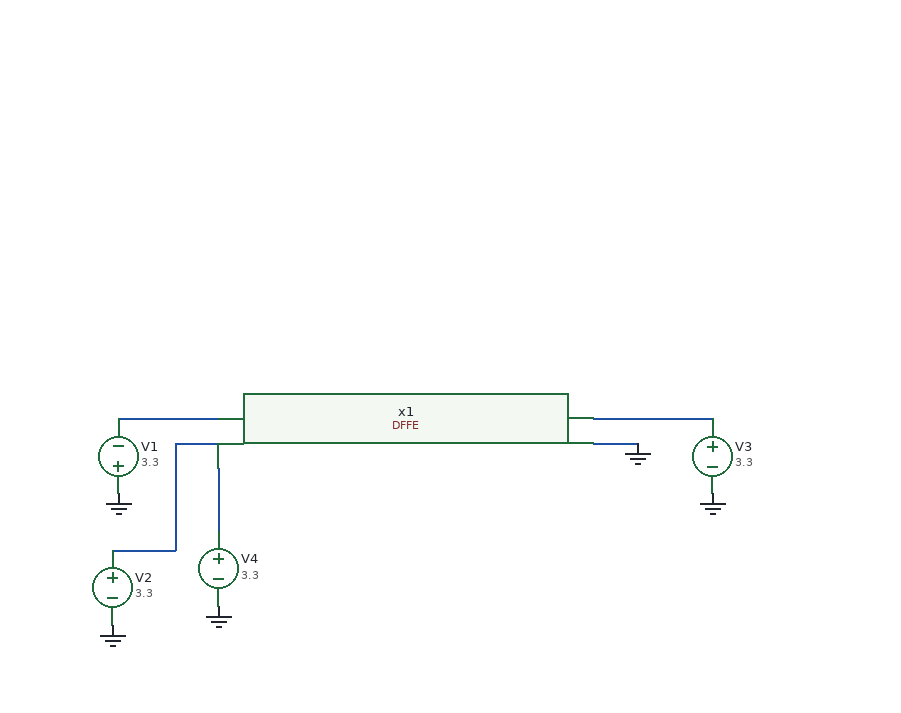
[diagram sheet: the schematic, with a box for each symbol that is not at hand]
v {xschem version=3.4.7 file_version=1.2}
G {}
K {}
V {}
S {}
E {}
N -1165 -2135 -1130 -2135 {lab=GND}
N -1545 -2155 -1465 -2155 {lab=#net1}
N -1550 -2050 -1500 -2050 {lab=#net2}
N -1500 -2135 -1500 -2050 {lab=#net2}
N -1500 -2135 -1465 -2135 {lab=#net2}
N -1165 -2155 -1070 -2155 {lab=#net3}
N -1465 -2115 -1465 -2065 {lab=#net4}
C {DFFE/DFFE.sym} -1315 -2125 0 0 {name=x1}
C {vsource.sym} -1550 -2020 0 0 {name=V2 value=3.3 savecurrent=false}
C {vsource.sym} -1070 -2125 0 0 {name=V3 value=3.3 savecurrent=false}
C {gnd.sym} -1545 -2095 0 0 {name=l1 lab=GND}
C {gnd.sym} -1550 -1990 0 0 {name=l2 lab=GND}
C {gnd.sym} -1070 -2095 0 0 {name=l3 lab=GND}
C {gnd.sym} -1130 -2135 0 0 {name=l4 lab=GND}
C {gnd.sym} -1465 -2005 0 0 {name=l5 lab=GND}
C {vsource.sym} -1465 -2035 0 0 {name=V4 value=3.3 savecurrent=false}
C {vsource.sym} -1545 -2125 2 0 {name=V1 value=3.3 savecurrent=false}
C {noconn.sym} -1250 -2420 0 0 {name=l6}
C {noconn.sym} -1165 -2115 2 0 {name=l7}
C {noconn.sym} -1165 -2095 2 0 {name=l8}
